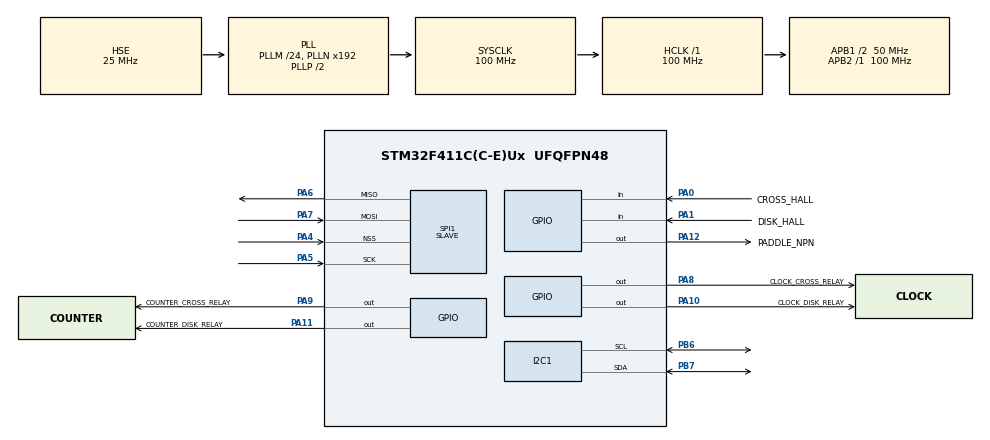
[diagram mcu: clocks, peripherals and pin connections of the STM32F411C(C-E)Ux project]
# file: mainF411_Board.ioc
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I2C1.I2C_Mode=I2C_Fast
Mcu.Family=STM32F4
Mcu.Name=STM32F411C(C-E)Ux
Mcu.Package=UFQFPN48
NVIC.PriorityGroup=NVIC_PRIORITYGROUP_4
PA0-WKUP.GPIO_Label=CROSS_HALL
PA0-WKUP.Signal=GPIO_Input
PA1.GPIO_Label=DISK_HALL
PA1.Signal=GPIO_Input
PA10.GPIO_Label=CLOCK_DISK_RELAY
PA10.Signal=GPIO_Output
PA11.GPIO_Label=COUNTER_DISK_RELAY
PA11.Signal=GPIO_Output
PA12.GPIO_Label=PADDLE_NPN
PA12.Signal=GPIO_Output
PA13.Mode=Serial_Wire
PA13.Signal=SYS_JTMS-SWDIO
PA14.Mode=Serial_Wire
PA14.Signal=SYS_JTCK-SWCLK
PA4.Mode=NSS_Signal_Hard_Input
PA4.Signal=SPI1_NSS
PA5.Mode=Full_Duplex_Slave
PA5.Signal=SPI1_SCK
PA6.Mode=Full_Duplex_Slave
PA6.Signal=SPI1_MISO
PA7.Mode=Full_Duplex_Slave
PA7.Signal=SPI1_MOSI
PA8.GPIO_Label=CLOCK_CROSS_RELAY
PA8.Signal=GPIO_Output
PA9.GPIO_Label=COUNTER_CROSS_RELAY
PA9.Signal=GPIO_Output
PB6.Mode=I2C
PB6.Signal=I2C1_SCL
PB7.Mode=I2C
PB7.Signal=I2C1_SDA
PH0\ -\ OSC_IN.Mode=HSE-External-Oscillator
PH0\ -\ OSC_IN.Signal=RCC_OSC_IN
PH1\ -\ OSC_OUT.Mode=HSE-External-Oscillator
PH1\ -\ OSC_OUT.Signal=RCC_OSC_OUT
ProjectManager.HeapSize=0x200
ProjectManager.StackSize=0x400
ProjectManager.TargetToolchain=STM32CubeIDE
RCC.48MHZClocksFreq_Value=50000000
RCC.AHBFreq_Value=100000000
RCC.APB1CLKDivider=RCC_HCLK_DIV2
RCC.APB1Freq_Value=50000000
RCC.APB1TimFreq_Value=100000000
RCC.APB2Freq_Value=100000000
RCC.APB2TimFreq_Value=100000000
RCC.CortexFreq_Value=100000000
RCC.HCLKFreq_Value=100000000
RCC.HSE_VALUE=25000000
RCC.HSI_VALUE=16000000
RCC.LSE_VALUE=32768
RCC.PLLM=24
RCC.PLLSourceVirtual=RCC_PLLSOURCE_HSE
RCC.SYSCLKFreq_VALUE=100000000
RCC.SYSCLKSource=RCC_SYSCLKSOURCE_PLLCLK
RCC.VCOOutputFreq_Value=200000000
SPI1.CRCCalculation=SPI_CRCCALCULATION_DISABLE
SPI1.Direction=SPI_DIRECTION_2LINES
SPI1.Mode=SPI_MODE_SLAVE
SPI1.VirtualNSS=VM_NSSHARD
SPI1.VirtualType=VM_SLAVE
board=custom

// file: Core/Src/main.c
/* USER CODE BEGIN Header */
/**
  ******************************************************************************
  * @file           : main.c
  * @brief          : Main program body
  ******************************************************************************
  * @attention
  *
  * Copyright (c) 2024 STMicroelectronics.
  * All rights reserved.
  *
  * This software is licensed under terms that can be found in the LICENSE file
  * in the root directory of this software component.
  * If no LICENSE file comes with this software, it is provided AS-IS.
  *
  ******************************************************************************
  */
/* USER CODE END Header */
#include "main.h"

I2C_HandleTypeDef hi2c1;

SPI_HandleTypeDef hspi1;

void SystemClock_Config(void);
static void MX_GPIO_Init(void);
static void MX_I2C1_Init(void);
static void MX_SPI1_Init(void);

int main(void)
{

  /* MCU Configuration--------------------------------------------------------*/

  /* Reset of all peripherals, Initializes the Flash interface and the Systick. */
  HAL_Init();

  /* Configure the system clock */
  SystemClock_Config();

  /* Initialize all configured peripherals */
  MX_GPIO_Init();
  MX_I2C1_Init();
  MX_SPI1_Init();

  /* Infinite loop */
  while (1)
  {

  }
}

void SystemClock_Config(void)
{
  RCC_OscInitTypeDef RCC_OscInitStruct = {0};
  RCC_ClkInitTypeDef RCC_ClkInitStruct = {0};

  /** Configure the main internal regulator output voltage
  */
  __HAL_RCC_PWR_CLK_ENABLE();
  __HAL_PWR_VOLTAGESCALING_CONFIG(PWR_REGULATOR_VOLTAGE_SCALE1);

  /** Initializes the RCC Oscillators according to the specified parameters
  * in the RCC_OscInitTypeDef structure.
  */
  RCC_OscInitStruct.OscillatorType = RCC_OSCILLATORTYPE_HSE;
  RCC_OscInitStruct.HSEState = RCC_HSE_ON;
  RCC_OscInitStruct.PLL.PLLState = RCC_PLL_ON;
  RCC_OscInitStruct.PLL.PLLSource = RCC_PLLSOURCE_HSE;
  RCC_OscInitStruct.PLL.PLLM = 24;
  RCC_OscInitStruct.PLL.PLLN = 192;
  RCC_OscInitStruct.PLL.PLLP = RCC_PLLP_DIV2;
  RCC_OscInitStruct.PLL.PLLQ = 4;
  if (HAL_RCC_OscConfig(&RCC_OscInitStruct) != HAL_OK)
  {
    Error_Handler();
  }

  /** Initializes the CPU, AHB and APB buses clocks
  */
  RCC_ClkInitStruct.ClockType = RCC_CLOCKTYPE_HCLK|RCC_CLOCKTYPE_SYSCLK
                              |RCC_CLOCKTYPE_PCLK1|RCC_CLOCKTYPE_PCLK2;
  RCC_ClkInitStruct.SYSCLKSource = RCC_SYSCLKSOURCE_PLLCLK;
  RCC_ClkInitStruct.AHBCLKDivider = RCC_SYSCLK_DIV1;
  RCC_ClkInitStruct.APB1CLKDivider = RCC_HCLK_DIV2;
  RCC_ClkInitStruct.APB2CLKDivider = RCC_HCLK_DIV1;

  if (HAL_RCC_ClockConfig(&RCC_ClkInitStruct, FLASH_LATENCY_3) != HAL_OK)
  {
    Error_Handler();
  }
}

static void MX_I2C1_Init(void)
{

  hi2c1.Instance = I2C1;
  hi2c1.Init.ClockSpeed = 400000;
  hi2c1.Init.DutyCycle = I2C_DUTYCYCLE_2;
  hi2c1.Init.OwnAddress1 = 0;
  hi2c1.Init.AddressingMode = I2C_ADDRESSINGMODE_7BIT;
  hi2c1.Init.DualAddressMode = I2C_DUALADDRESS_DISABLE;
  hi2c1.Init.OwnAddress2 = 0;
  hi2c1.Init.GeneralCallMode = I2C_GENERALCALL_DISABLE;
  hi2c1.Init.NoStretchMode = I2C_NOSTRETCH_DISABLE;
  if (HAL_I2C_Init(&hi2c1) != HAL_OK)
  {
    Error_Handler();
  }

}

static void MX_SPI1_Init(void)
{

  /* SPI1 parameter configuration*/
  hspi1.Instance = SPI1;
  hspi1.Init.Mode = SPI_MODE_SLAVE;
  hspi1.Init.Direction = SPI_DIRECTION_2LINES;
  hspi1.Init.DataSize = SPI_DATASIZE_8BIT;
  hspi1.Init.CLKPolarity = SPI_POLARITY_LOW;
  hspi1.Init.CLKPhase = SPI_PHASE_1EDGE;
  hspi1.Init.NSS = SPI_NSS_HARD_INPUT;
  hspi1.Init.FirstBit = SPI_FIRSTBIT_MSB;
  hspi1.Init.TIMode = SPI_TIMODE_DISABLE;
  hspi1.Init.CRCCalculation = SPI_CRCCALCULATION_DISABLE;
  hspi1.Init.CRCPolynomial = 10;
  if (HAL_SPI_Init(&hspi1) != HAL_OK)
  {
    Error_Handler();
  }

}

static void MX_GPIO_Init(void)
{
  GPIO_InitTypeDef GPIO_InitStruct = {0};

  /* GPIO Ports Clock Enable */
  __HAL_RCC_GPIOH_CLK_ENABLE();
  __HAL_RCC_GPIOA_CLK_ENABLE();
  __HAL_RCC_GPIOB_CLK_ENABLE();

  /*Configure GPIO pin Output Level */
  HAL_GPIO_WritePin(GPIOA, ACTIVATE_CROSS_RELAY_Pin|DEACTIVATE_CROSS_RELAY_Pin|ACTIVATE_DISK_RELAY_Pin|DEACTIVATE_CROSS_RELAYA11_Pin
                          |PADDLE_NPN_Pin, GPIO_PIN_RESET);

  /*Configure GPIO pins : CROSS_HALL_Pin DISK_HALL_Pin */
  GPIO_InitStruct.Pin = CROSS_HALL_Pin|DISK_HALL_Pin;
  GPIO_InitStruct.Mode = GPIO_MODE_INPUT;
  GPIO_InitStruct.Pull = GPIO_NOPULL;
  HAL_GPIO_Init(GPIOA, &GPIO_InitStruct);

  /*Configure GPIO pins : ACTIVATE_CROSS_RELAY_Pin DEACTIVATE_CROSS_RELAY_Pin ACTIVATE_DISK_RELAY_Pin DEACTIVATE_CROSS_RELAYA11_Pin
                           PADDLE_NPN_Pin */
  GPIO_InitStruct.Pin = ACTIVATE_CROSS_RELAY_Pin|DEACTIVATE_CROSS_RELAY_Pin|ACTIVATE_DISK_RELAY_Pin|DEACTIVATE_CROSS_RELAYA11_Pin
                          |PADDLE_NPN_Pin;
  GPIO_InitStruct.Mode = GPIO_MODE_OUTPUT_PP;
  GPIO_InitStruct.Pull = GPIO_NOPULL;
  GPIO_InitStruct.Speed = GPIO_SPEED_FREQ_LOW;
  HAL_GPIO_Init(GPIOA, &GPIO_InitStruct);

}

void Error_Handler(void)
{
  __disable_irq();
  while (1)
  {
  }
}
